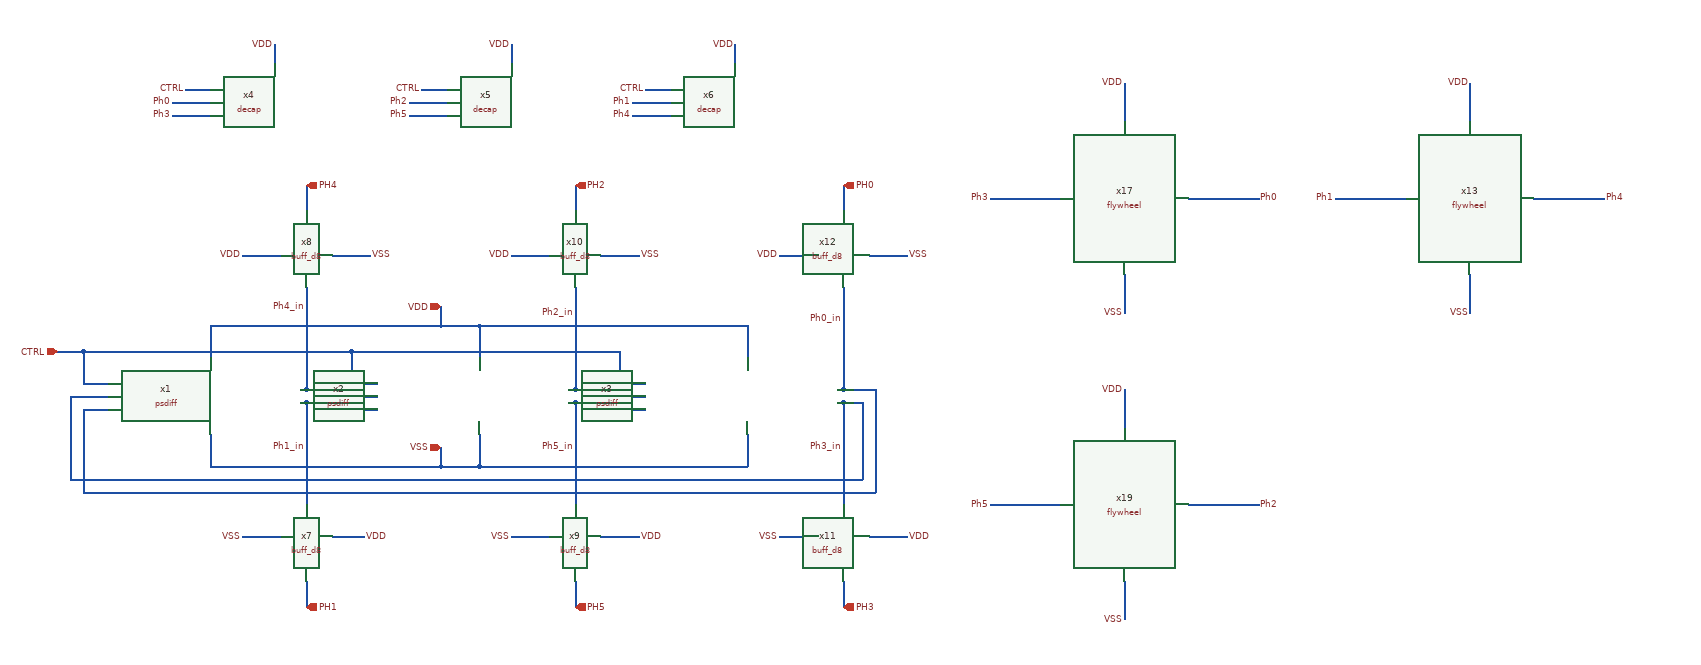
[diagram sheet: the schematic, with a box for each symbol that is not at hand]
v {xschem version=3.4.8RC file_version=1.3}
G {}
K {}
V {}
S {}
F {}
E {}
N 480 -280 480 -230 {lab=VDD}
N 840 -280 900 -280 {lab=VDD}
N 900 -280 900 -230 {lab=VDD}
N 900 -280 1320 -280 {lab=VDD}
N 1320 -280 1320 -230 {lab=VDD}
N 480 -110 480 -60 {lab=VSS}
N 900 -110 900 -60 {lab=VSS}
N 1320 -110 1320 -60 {lab=VSS}
N 840 -60 900 -60 {lab=VSS}
N 900 -60 1320 -60 {lab=VSS}
N 630 -180 660 -180 {lab=Ph4_in}
N 700 -150 740 -150 {lab=Ph4_in}
N 660 -180 700 -150 {lab=Ph4_in}
N 630 -160 660 -160 {lab=Ph1_in}
N 700 -170 740 -170 {lab=Ph1_in}
N 660 -160 700 -170 {lab=Ph1_in}
N 1050 -180 1080 -180 {lab=Ph2_in}
N 1120 -150 1160 -150 {lab=Ph2_in}
N 1080 -180 1120 -150 {lab=Ph2_in}
N 1050 -160 1080 -160 {lab=Ph5_in}
N 1120 -170 1160 -170 {lab=Ph5_in}
N 1080 -160 1120 -170 {lab=Ph5_in}
N 280 -190 320 -190 {lab=CTRL}
N 280 -240 280 -190 {lab=CTRL}
N 280 -240 700 -240 {lab=CTRL}
N 700 -190 740 -190 {lab=CTRL}
N 700 -240 700 -190 {lab=CTRL}
N 1120 -190 1160 -190 {lab=CTRL}
N 1120 -240 1120 -190 {lab=CTRL}
N 700 -240 1120 -240 {lab=CTRL}
N 280 -150 320 -150 {lab=Ph0_in}
N 1470 -160 1500 -160 {lab=Ph3_in}
N 1470 -180 1520 -180 {lab=Ph0_in}
N 1520 -180 1520 -20 {lab=Ph0_in}
N 280 -20 1520 -20 {lab=Ph0_in}
N 280 -150 280 -20 {lab=Ph0_in}
N 1500 -160 1500 -40 {lab=Ph3_in}
N 260 -40 1500 -40 {lab=Ph3_in}
N 260 -170 260 -40 {lab=Ph3_in}
N 260 -170 320 -170 {lab=Ph3_in}
N 840 -310 840 -280 {lab=VDD}
N 480 -280 840 -280 {lab=VDD}
N 840 -90 840 -60 {lab=VSS}
N 480 -60 840 -60 {lab=VSS}
N 240 -240 280 -240 {lab=CTRL}
N 630 -160 630 0 {lab=Ph1_in}
N 580 -720 580 -690 {lab=VDD}
N 440 -650 480 -650 {lab=CTRL}
N 420 -630 480 -630 {lab=Ph0}
N 420 -610 480 -610 {lab=Ph3}
N 950 -720 950 -690 {lab=VDD}
N 810 -650 850 -650 {lab=CTRL}
N 790 -630 850 -630 {lab=Ph2}
N 790 -610 850 -610 {lab=Ph5}
N 1300 -720 1300 -690 {lab=VDD}
N 1160 -650 1200 -650 {lab=CTRL}
N 1140 -630 1200 -630 {lab=Ph1}
N 1140 -610 1200 -610 {lab=Ph4}
N 630 120 630 160 {lab=PH1}
N 530 50 590 50 {lab=VSS}
N 630 -340 630 -180 {lab=Ph4_in}
N 630 -500 630 -460 {lab=PH4}
N 670 -390 730 -390 {lab=VSS}
N 530 -390 590 -390 {lab=VDD}
N 1050 -160 1050 0 {lab=Ph5_in}
N 1050 -500 1050 -460 {lab=PH2}
N 950 50 1010 50 {lab=VSS}
N 1090 50 1150 50 {lab=VDD}
N 1050 -340 1050 -180 {lab=Ph2_in}
N 1090 -390 1150 -390 {lab=VSS}
N 950 -390 1010 -390 {lab=VDD}
N 1050 120 1050 160 {lab=PH5}
N 1470 -160 1470 0 {lab=Ph3_in}
N 1470 120 1470 160 {lab=PH3}
N 1370 50 1430 50 {lab=VSS}
N 1510 50 1570 50 {lab=VDD}
N 1470 -340 1470 -180 {lab=Ph0_in}
N 1510 -390 1570 -390 {lab=VSS}
N 1370 -390 1430 -390 {lab=VDD}
N 1470 -500 1470 -460 {lab=PH0}
N 620 -180 630 -180 {lab=Ph4_in}
N 620 -160 630 -160 {lab=Ph1_in}
N 1040 -180 1050 -180 {lab=Ph2_in}
N 1040 -160 1050 -160 {lab=Ph5_in}
N 1460 -180 1470 -180 {lab=Ph0_in}
N 1460 -160 1470 -160 {lab=Ph3_in}
N 670 50 720 50 {lab=VDD}
N 1910 -660 1910 -600 {lab=VDD}
N 1910 -360 1910 -300 {lab=VSS}
N 1700 -480 1810 -480 {lab=Ph3}
N 2010 -480 2120 -480 {lab=Ph0}
N 2450 -660 2450 -600 {lab=VDD}
N 2240 -480 2350 -480 {lab=Ph1}
N 2550 -480 2660 -480 {lab=Ph4}
N 1910 -180 1910 -120 {lab=VDD}
N 1910 120 1910 180 {lab=VSS}
N 1700 0 1810 0 {lab=Ph5}
N 2010 0 2120 0 {lab=Ph2}
N 2450 -360 2450 -300 {lab=VSS}
C {psdiff/psdiff.sym} 310 -110 0 0 {name=x1}
C {psdiff/psdiff.sym} 730 -110 0 0 {name=x2}
C {psdiff/psdiff.sym} 1150 -110 0 0 {name=x3}
C {iopin.sym} 840 -310 0 0 {name=p1 lab=VDD}
C {iopin.sym} 840 -90 2 0 {name=p2 lab=VSS}
C {ipin.sym} 240 -240 0 0 {name=p3 lab=CTRL}
C {opin.sym} 1470 -500 3 0 {name=p5 lab=PH0}
C {opin.sym} 1050 -500 3 0 {name=p6 lab=PH2}
C {opin.sym} 1050 160 1 0 {name=p7 lab=PH5}
C {opin.sym} 630 160 1 0 {name=p8 lab=PH1}
C {opin.sym} 630 -500 3 0 {name=p9 lab=PH4}
C {decap/decap.sym} 450 -570 0 0 {name=x4
}
C {lab_pin.sym} 580 -720 0 0 {name=p10 sig_type=std_logic lab=VDD}
C {lab_pin.sym} 440 -650 0 0 {name=p11 sig_type=std_logic lab=CTRL}
C {lab_pin.sym} 420 -630 0 0 {name=p12 sig_type=std_logic lab=Ph0}
C {lab_pin.sym} 420 -610 0 0 {name=p13 sig_type=std_logic lab=Ph3}
C {decap/decap.sym} 820 -570 0 0 {name=x5
}
C {lab_pin.sym} 950 -720 0 0 {name=p14 sig_type=std_logic lab=VDD}
C {lab_pin.sym} 810 -650 0 0 {name=p15 sig_type=std_logic lab=CTRL}
C {lab_pin.sym} 790 -630 0 0 {name=p16 sig_type=std_logic lab=Ph2}
C {lab_pin.sym} 790 -610 0 0 {name=p17 sig_type=std_logic lab=Ph5}
C {decap/decap.sym} 1170 -570 0 0 {name=x6
}
C {lab_pin.sym} 1300 -720 0 0 {name=p18 sig_type=std_logic lab=VDD}
C {lab_pin.sym} 1160 -650 0 0 {name=p19 sig_type=std_logic lab=CTRL}
C {lab_pin.sym} 1140 -630 0 0 {name=p20 sig_type=std_logic lab=Ph1}
C {lab_pin.sym} 1140 -610 0 0 {name=p21 sig_type=std_logic lab=Ph4}
C {buff_d8/buff_d8.sym} 630 50 1 0 {name=x7
}
C {lab_pin.sym} 720 50 2 0 {name=p22 sig_type=std_logic lab=VDD}
C {lab_pin.sym} 530 50 0 0 {name=p23 sig_type=std_logic lab=VSS}
C {buff_d8/buff_d8.sym} 630 -390 3 0 {name=x8
}
C {lab_pin.sym} 530 -390 0 0 {name=p24 sig_type=std_logic lab=VDD}
C {lab_pin.sym} 730 -390 2 0 {name=p25 sig_type=std_logic lab=VSS}
C {buff_d8/buff_d8.sym} 1050 50 1 0 {name=x9
}
C {lab_pin.sym} 1150 50 2 0 {name=p26 sig_type=std_logic lab=VDD}
C {lab_pin.sym} 950 50 0 0 {name=p27 sig_type=std_logic lab=VSS}
C {buff_d8/buff_d8.sym} 1050 -390 3 0 {name=x10
}
C {lab_pin.sym} 950 -390 0 0 {name=p28 sig_type=std_logic lab=VDD}
C {lab_pin.sym} 1150 -390 2 0 {name=p29 sig_type=std_logic lab=VSS}
C {buff_d8/buff_d8.sym} 1470 50 1 0 {name=x11
}
C {lab_pin.sym} 1570 50 2 0 {name=p30 sig_type=std_logic lab=VDD}
C {lab_pin.sym} 1370 50 0 0 {name=p31 sig_type=std_logic lab=VSS}
C {opin.sym} 1470 160 1 0 {name=p32 lab=PH3}
C {buff_d8/buff_d8.sym} 1470 -390 3 0 {name=x12
}
C {lab_pin.sym} 1370 -390 0 0 {name=p4 sig_type=std_logic lab=VDD}
C {lab_pin.sym} 1570 -390 2 0 {name=p33 sig_type=std_logic lab=VSS}
C {lab_pin.sym} 1910 -660 1 0 {name=p34 sig_type=std_logic lab=VDD}
C {lab_pin.sym} 1910 -300 1 1 {name=p37 sig_type=std_logic lab=VSS}
C {lab_pin.sym} 2450 -660 1 0 {name=p38 sig_type=std_logic lab=VDD}
C {lab_pin.sym} 2450 -300 1 1 {name=p41 sig_type=std_logic lab=VSS}
C {lab_pin.sym} 1700 -480 0 0 {name=p42 sig_type=std_logic lab=Ph3}
C {lab_pin.sym} 2120 -480 2 0 {name=p43 sig_type=std_logic lab=Ph0}
C {lab_pin.sym} 2240 -480 0 0 {name=p44 sig_type=std_logic lab=Ph1}
C {lab_pin.sym} 2660 -480 2 0 {name=p45 sig_type=std_logic lab=Ph4}
C {lab_pin.sym} 1910 -180 1 0 {name=p46 sig_type=std_logic lab=VDD}
C {lab_pin.sym} 1910 180 1 1 {name=p49 sig_type=std_logic lab=VSS}
C {lab_pin.sym} 1700 0 0 0 {name=p50 sig_type=std_logic lab=Ph5}
C {lab_pin.sym} 2120 0 2 0 {name=p51 sig_type=std_logic lab=Ph2}
C {flywheel/flywheel.sym} 1910 0 0 0 {name=x19}
C {flywheel/flywheel.sym} 1910 -480 0 0 {name=x17}
C {flywheel/flywheel.sym} 2450 -480 0 0 {name=x13}
C {lab_wire.sym} 1470 -290 0 0 {name=p52 sig_type=std_logic lab=Ph0_in}
C {lab_wire.sym} 1470 -90 0 0 {name=p35 sig_type=std_logic lab=Ph3_in}
C {lab_wire.sym} 1050 -90 0 0 {name=p36 sig_type=std_logic lab=Ph5_in}
C {lab_wire.sym} 1050 -300 0 0 {name=p39 sig_type=std_logic lab=Ph2_in}
C {lab_wire.sym} 630 -310 0 0 {name=p40 sig_type=std_logic lab=Ph4_in}
C {lab_wire.sym} 630 -90 0 0 {name=p47 sig_type=std_logic lab=Ph1_in}
